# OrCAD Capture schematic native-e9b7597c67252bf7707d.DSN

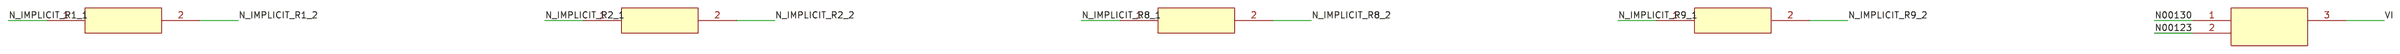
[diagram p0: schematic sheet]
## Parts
R1  100K
R2  100K
R8  1K
R9  1K
U3  LM317_TO-220

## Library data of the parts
R1 = OBS_R1
R2 = OBS_R2
R8 = OBS_R8
R9 = OBS_R9
U3 = OBS_U3

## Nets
N_IMPLICIT_R1_1: R1.1
N_IMPLICIT_R1_2: R1.2
N_IMPLICIT_R2_1: R2.1
N_IMPLICIT_R2_2: R2.2
N_IMPLICIT_R8_1: R8.1
N_IMPLICIT_R8_2: R8.2
N_IMPLICIT_R9_1: R9.1
N_IMPLICIT_R9_2: R9.2
VI: U3.3

Not connected (* = marked no-connect by the designer): U3 1 2
